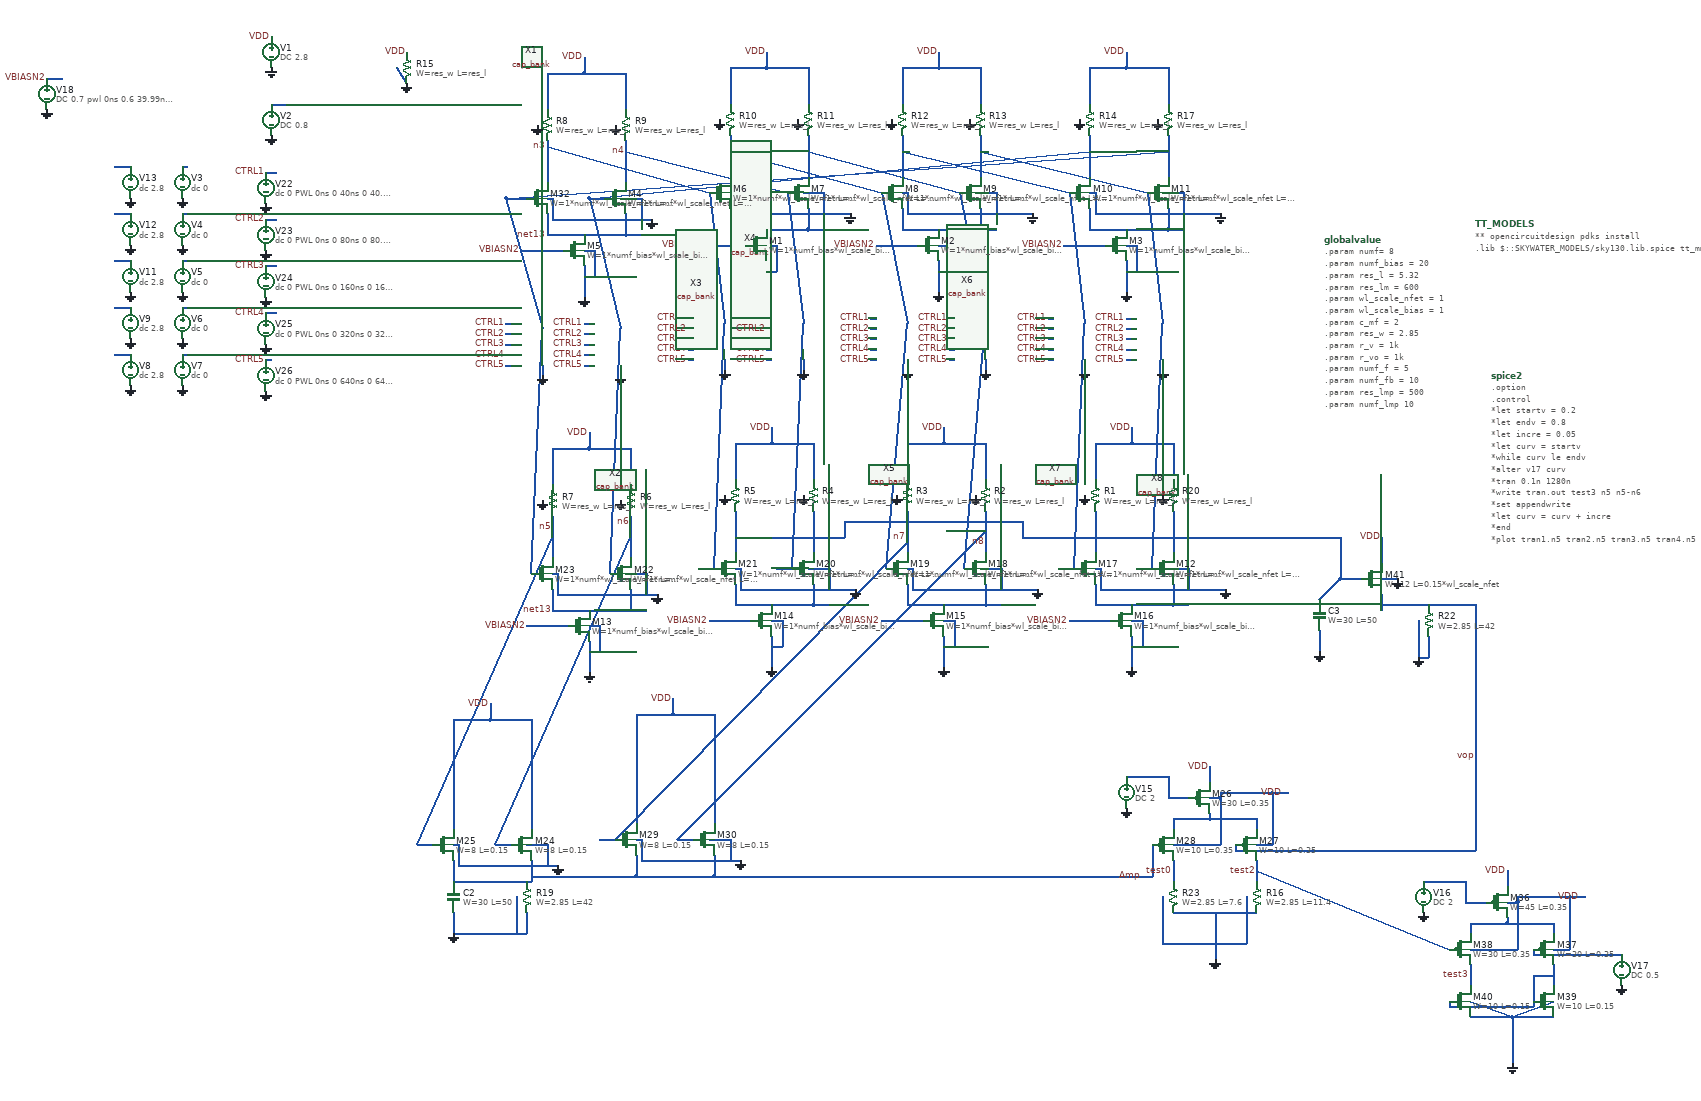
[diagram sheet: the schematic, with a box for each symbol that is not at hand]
v {xschem version=3.0.0 file_version=1.2 }
G {}
K {}
V {}
S {}
E {}
N 520 -180 520 -140 {
lab=GND}
N 450 -240 520 -240 {
lab=net13}
N 450 -280 450 -240 {
lab=net13}
N 520 -240 600 -240 {
lab=net13}
N 600 -280 600 -240 {
lab=net13}
N 600 -420 600 -340 {
lab=n4}
N 600 -550 600 -480 {
lab=VDD}
N 520 -550 600 -550 {
lab=VDD}
N 520 -580 520 -550 {
lab=VDD}
N 450 -550 520 -550 {
lab=VDD}
N 450 -550 450 -480 {
lab=VDD}
N 450 -420 450 -340 {
lab=n3}
N 380 -310 410 -310 {
lab=#net1}
N 530 -310 560 -310 {
lab=#net2}
N 400 -210 480 -210 {
lab=VBIASN2}
N 450 -310 460 -310 {
lab=GND}
N 520 -140 520 -120 {
lab=GND}
N 520 -210 540 -210 {
lab=GND}
N 540 -210 540 -160 {
lab=GND}
N 520 -160 540 -160 {
lab=GND}
N 590 -310 600 -310 {
lab=GND}
N 600 -310 630 -310 {
lab=GND}
N 600 -240 630 -240 {
lab=net13}
N 870 -190 870 -150 {
lab=GND}
N 800 -250 870 -250 {
lab=#net3}
N 800 -290 800 -250 {
lab=#net3}
N 870 -250 950 -250 {
lab=#net3}
N 950 -290 950 -250 {
lab=#net3}
N 950 -430 950 -350 {
lab=#net4}
N 950 -560 950 -490 {
lab=VDD}
N 870 -560 950 -560 {
lab=VDD}
N 870 -590 870 -560 {
lab=VDD}
N 800 -560 870 -560 {
lab=VDD}
N 800 -560 800 -490 {
lab=VDD}
N 800 -430 800 -350 {
lab=#net5}
N 750 -220 830 -220 {
lab=VBIASN2}
N 800 -320 810 -320 {
lab=GND}
N 870 -150 870 -130 {
lab=GND}
N 870 -220 890 -220 {
lab=GND}
N 890 -220 890 -170 {
lab=GND}
N 870 -170 890 -170 {
lab=GND}
N 940 -320 950 -320 {
lab=GND}
N 950 -320 980 -320 {
lab=GND}
N 950 -250 980 -250 {
lab=#net3}
N 1200 -190 1200 -150 {
lab=GND}
N 1130 -250 1200 -250 {
lab=#net6}
N 1130 -290 1130 -250 {
lab=#net6}
N 1200 -250 1280 -250 {
lab=#net6}
N 1280 -290 1280 -250 {
lab=#net6}
N 1280 -430 1280 -350 {
lab=#net7}
N 1280 -560 1280 -490 {
lab=VDD}
N 1200 -560 1280 -560 {
lab=VDD}
N 1200 -590 1200 -560 {
lab=VDD}
N 1130 -560 1200 -560 {
lab=VDD}
N 1130 -560 1130 -490 {
lab=VDD}
N 1130 -430 1130 -350 {
lab=#net8}
N 1080 -220 1160 -220 {
lab=VBIASN2}
N 1130 -320 1140 -320 {
lab=GND}
N 1200 -150 1200 -130 {
lab=GND}
N 1200 -220 1220 -220 {
lab=GND}
N 1220 -220 1220 -170 {
lab=GND}
N 1200 -170 1220 -170 {
lab=GND}
N 1270 -320 1280 -320 {
lab=GND}
N 1280 -320 1310 -320 {
lab=GND}
N 1280 -250 1310 -250 {
lab=#net6}
N 460 -310 460 -270 {
lab=GND}
N 460 -270 650 -270 {
lab=GND}
N 630 -310 630 -270 {
lab=GND}
N 810 -320 810 -280 {
lab=GND}
N 810 -280 1030 -280 {
lab=GND}
N 980 -320 980 -280 {
lab=GND}
N 1140 -320 1140 -280 {
lab=GND}
N 1140 -280 1380 -280 {
lab=GND}
N 1310 -320 1310 -280 {
lab=GND}
N 1560 -190 1560 -150 {
lab=GND}
N 1490 -250 1560 -250 {
lab=#net9}
N 1490 -290 1490 -250 {
lab=#net9}
N 1560 -250 1640 -250 {
lab=#net9}
N 1640 -290 1640 -250 {
lab=#net9}
N 1640 -430 1640 -350 {
lab=#net1}
N 1640 -560 1640 -490 {
lab=VDD}
N 1560 -560 1640 -560 {
lab=VDD}
N 1560 -590 1560 -560 {
lab=VDD}
N 1490 -560 1560 -560 {
lab=VDD}
N 1490 -560 1490 -490 {
lab=VDD}
N 1490 -430 1490 -350 {
lab=#net2}
N 1440 -220 1520 -220 {
lab=VBIASN2}
N 1490 -320 1500 -320 {
lab=GND}
N 1560 -150 1560 -130 {
lab=GND}
N 1560 -220 1580 -220 {
lab=GND}
N 1580 -220 1580 -170 {
lab=GND}
N 1560 -170 1580 -170 {
lab=GND}
N 1630 -320 1640 -320 {
lab=GND}
N 1640 -320 1670 -320 {
lab=GND}
N 1640 -250 1670 -250 {
lab=#net9}
N 1500 -320 1500 -280 {
lab=GND}
N 1500 -280 1740 -280 {
lab=GND}
N 1670 -320 1670 -280 {
lab=GND}
N -80 -490 -50 -490 {
lab=#net10}
N -250 -370 -240 -370 {
lab=#net11}
N -250 -280 -240 -280 {
lab=#net12}
N -250 -190 -240 -190 {
lab=#net14}
N -250 -100 -240 -100 {
lab=#net15}
N -250 -10 -240 -10 {
lab=#net16}
N 530 540 530 580 {
lab=GND}
N 460 480 530 480 {
lab=net13}
N 460 440 460 480 {
lab=net13}
N 530 480 610 480 {
lab=net13}
N 610 440 610 480 {
lab=net13}
N 610 300 610 380 {
lab=n6}
N 610 170 610 240 {
lab=VDD}
N 530 170 610 170 {
lab=VDD}
N 530 140 530 170 {
lab=VDD}
N 460 170 530 170 {
lab=VDD}
N 460 170 460 240 {
lab=VDD}
N 460 300 460 380 {
lab=n5}
N 410 510 490 510 {
lab=VBIASN2}
N 460 410 470 410 {
lab=GND}
N 530 580 530 600 {
lab=GND}
N 530 510 550 510 {
lab=GND}
N 550 510 550 560 {
lab=GND}
N 530 560 550 560 {
lab=GND}
N 600 410 610 410 {
lab=GND}
N 610 410 640 410 {
lab=GND}
N 610 480 640 480 {
lab=net13}
N 880 530 880 570 {
lab=GND}
N 810 470 880 470 {
lab=#net17}
N 810 430 810 470 {
lab=#net17}
N 880 470 960 470 {
lab=#net17}
N 960 430 960 470 {
lab=#net17}
N 960 290 960 370 {
lab=#net18}
N 960 160 960 230 {
lab=VDD}
N 880 160 960 160 {
lab=VDD}
N 880 130 880 160 {
lab=VDD}
N 810 160 880 160 {
lab=VDD}
N 810 160 810 230 {
lab=VDD}
N 810 290 810 370 {
lab=#net18}
N 740 400 770 400 {
lab=n3}
N 890 400 920 400 {
lab=n4}
N 760 500 840 500 {
lab=VBIASN2}
N 810 400 820 400 {
lab=GND}
N 880 570 880 590 {
lab=GND}
N 880 500 900 500 {
lab=GND}
N 900 500 900 550 {
lab=GND}
N 880 550 900 550 {
lab=GND}
N 950 400 960 400 {
lab=GND}
N 960 400 990 400 {
lab=GND}
N 960 470 990 470 {
lab=#net17}
N 1210 530 1210 570 {
lab=GND}
N 1140 470 1210 470 {
lab=#net19}
N 1140 430 1140 470 {
lab=#net19}
N 1210 470 1290 470 {
lab=#net19}
N 1290 430 1290 470 {
lab=#net19}
N 1290 290 1290 370 {
lab=n8}
N 1290 160 1290 230 {
lab=VDD}
N 1210 160 1290 160 {
lab=VDD}
N 1210 130 1210 160 {
lab=VDD}
N 1140 160 1210 160 {
lab=VDD}
N 1140 160 1140 230 {
lab=VDD}
N 1140 290 1140 370 {
lab=n7}
N 1090 500 1170 500 {
lab=VBIASN2}
N 1140 400 1150 400 {
lab=GND}
N 1210 570 1210 590 {
lab=GND}
N 1210 500 1230 500 {
lab=GND}
N 1230 500 1230 550 {
lab=GND}
N 1210 550 1230 550 {
lab=GND}
N 1280 400 1290 400 {
lab=GND}
N 1290 400 1320 400 {
lab=GND}
N 1290 470 1320 470 {
lab=#net19}
N 470 410 470 450 {
lab=GND}
N 470 450 660 450 {
lab=GND}
N 640 410 640 450 {
lab=GND}
N 820 400 820 440 {
lab=GND}
N 820 440 1040 440 {
lab=GND}
N 990 400 990 440 {
lab=GND}
N 1150 400 1150 440 {
lab=GND}
N 1150 440 1390 440 {
lab=GND}
N 1320 400 1320 440 {
lab=GND}
N 1570 530 1570 570 {
lab=GND}
N 1500 470 1570 470 {
lab=#net20}
N 1500 430 1500 470 {
lab=#net20}
N 1570 470 1650 470 {
lab=#net20}
N 1650 430 1650 470 {
lab=#net20}
N 1650 290 1650 370 {
lab=#net18}
N 1650 160 1650 230 {
lab=VDD}
N 1570 160 1650 160 {
lab=VDD}
N 1570 130 1570 160 {
lab=VDD}
N 1500 160 1570 160 {
lab=VDD}
N 1500 160 1500 230 {
lab=VDD}
N 1500 290 1500 370 {
lab=#net18}
N 1430 400 1460 400 {
lab=#net8}
N 1580 400 1610 400 {
lab=#net7}
N 1450 500 1530 500 {
lab=VBIASN2}
N 1500 400 1510 400 {
lab=GND}
N 1570 570 1570 590 {
lab=GND}
N 1570 500 1590 500 {
lab=GND}
N 1590 500 1590 550 {
lab=GND}
N 1570 550 1590 550 {
lab=GND}
N 1640 400 1650 400 {
lab=GND}
N 1650 400 1680 400 {
lab=GND}
N 1650 470 1680 470 {
lab=#net20}
N 1510 400 1510 440 {
lab=GND}
N 1510 440 1750 440 {
lab=GND}
N 1680 400 1680 440 {
lab=GND}
N 420 410 440 -60 {
lab=#net1}
N 570 410 590 -60 {
lab=#net2}
N 770 400 790 -70 {
lab=n3}
N 920 400 940 -70 {
lab=n4}
N 1100 400 1140 -70 {
lab=#net5}
N 1250 400 1290 -70 {
lab=#net4}
N 1460 400 1480 -70 {
lab=#net8}
N 1610 400 1630 -70 {
lab=#net7}
N 810 340 960 340 {
lab=#net18}
N 1500 340 1650 340 {
lab=#net18}
N 270 960 270 1000 {
lab=Amp}
N 340 1000 420 1000 {
lab=Amp}
N 420 960 420 1000 {
lab=Amp}
N 420 820 420 900 {
lab=VDD}
N 420 690 420 760 {
lab=VDD}
N 340 690 420 690 {
lab=VDD}
N 340 660 340 690 {
lab=VDD}
N 270 690 340 690 {
lab=VDD}
N 270 690 270 760 {
lab=VDD}
N 270 820 270 900 {
lab=VDD}
N 200 930 230 930 {
lab=n5}
N 350 930 380 930 {
lab=n6}
N 270 930 280 930 {
lab=GND}
N 410 930 420 930 {
lab=GND}
N 420 930 450 930 {
lab=GND}
N 280 930 280 970 {
lab=GND}
N 280 970 470 970 {
lab=GND}
N 450 930 450 970 {
lab=GND}
N 270 1060 270 1100 {
lab=GND}
N 270 1000 340 1000 {
lab=Amp}
N 270 760 270 820 {
lab=VDD}
N 420 760 420 820 {
lab=VDD}
N 410 1060 410 1100 {
lab=GND}
N 340 1100 410 1100 {
lab=GND}
N 270 1100 340 1100 {
lab=GND}
N 620 950 620 990 {
lab=Amp}
N 690 990 770 990 {
lab=Amp}
N 770 950 770 990 {
lab=Amp}
N 770 810 770 890 {
lab=VDD}
N 770 680 770 750 {
lab=VDD}
N 690 680 770 680 {
lab=VDD}
N 690 650 690 680 {
lab=VDD}
N 620 680 690 680 {
lab=VDD}
N 620 680 620 750 {
lab=VDD}
N 620 810 620 890 {
lab=VDD}
N 550 920 580 920 {
lab=n7}
N 700 920 730 920 {
lab=n8}
N 620 920 630 920 {
lab=GND}
N 760 920 770 920 {
lab=GND}
N 770 920 800 920 {
lab=GND}
N 630 920 630 960 {
lab=GND}
N 630 960 820 960 {
lab=GND}
N 800 920 800 960 {
lab=GND}
N 620 990 690 990 {
lab=Amp}
N 620 750 620 810 {
lab=VDD}
N 770 750 770 810 {
lab=VDD}
N 420 990 620 990 {
lab=Amp}
N 770 990 950 990 {
lab=Amp}
N 1720 780 1720 810 {
lab=VDD}
N 1560 800 1640 800 {
lab=#net21}
N 1640 800 1640 840 {
lab=#net21}
N 1640 840 1680 840 {
lab=#net21}
N 1460 990 1610 990 {
lab=Amp}
N 1610 930 1610 990 {
lab=Amp}
N 1720 870 1720 880 {
lab=#net22}
N 1650 880 1720 880 {
lab=#net22}
N 1650 880 1650 900 {
lab=#net22}
N 1720 880 1810 880 {
lab=#net22}
N 1810 880 1810 900 {
lab=#net22}
N 1650 960 1650 1000 {
lab=test0}
N 1810 960 1810 1000 {
lab=test2}
N 1650 1060 1810 1060 {
lab=GND}
N 1730 1060 1730 1080 {
lab=GND}
N 1840 830 1870 830 {
lab=VDD}
N 1840 830 1840 930 {
lab=VDD}
N 1810 930 1840 930 {
lab=VDD}
N 1740 830 1840 830 {
lab=VDD}
N 1740 830 1740 840 {
lab=VDD}
N 1720 840 1740 840 {
lab=VDD}
N 1740 840 1740 930 {
lab=VDD}
N 1650 930 1740 930 {
lab=VDD}
N 1730 1080 1730 1150 {
lab=GND}
N 2290 980 2290 1010 {
lab=VDD}
N 2130 1000 2210 1000 {
lab=#net23}
N 2210 1000 2210 1040 {
lab=#net23}
N 2210 1040 2250 1040 {
lab=#net23}
N 2290 1070 2290 1080 {
lab=#net24}
N 2220 1080 2290 1080 {
lab=#net24}
N 2220 1080 2220 1100 {
lab=#net24}
N 2290 1080 2380 1080 {
lab=#net24}
N 2380 1080 2380 1100 {
lab=#net24}
N 2340 1130 2340 1140 {
lab=#net25}
N 2340 1140 2510 1140 {
lab=#net25}
N 2220 1160 2220 1200 {
lab=test3}
N 2380 1160 2380 1200 {
lab=#net26}
N 2220 1260 2380 1260 {
lab=GND}
N 2300 1260 2300 1280 {
lab=GND}
N 2410 1030 2440 1030 {
lab=VDD}
N 2410 1030 2410 1130 {
lab=VDD}
N 2380 1130 2410 1130 {
lab=VDD}
N 2310 1030 2410 1030 {
lab=VDD}
N 2310 1030 2310 1040 {
lab=VDD}
N 2290 1040 2310 1040 {
lab=VDD}
N 2310 1040 2310 1130 {
lab=VDD}
N 2220 1130 2310 1130 {
lab=VDD}
N 2300 1280 2300 1350 {
lab=GND}
N 2340 1180 2340 1230 {
lab=#net26}
N 2340 1180 2380 1180 {
lab=#net26}
N 2340 1230 2340 1240 {
lab=#net26}
N 2180 1240 2340 1240 {
lab=#net26}
N 2180 1230 2180 1240 {
lab=#net26}
N 2220 1230 2300 1260 {
lab=GND}
N 2300 1260 2380 1230 {
lab=GND}
N 1810 980 2180 1130 {
lab=test2}
N 2140 530 2140 570 {
lab=GND}
N 2050 340 2050 380 {
lab=VDD}
N 2050 380 2050 390 {
lab=VDD}
N 2050 450 2050 480 {
lab=vop}
N 2050 470 2140 470 {
lab=vop}
N 2050 420 2080 420 {
lab=GND}
N 1930 520 1930 560 {
lab=GND}
N 2140 470 2230 470 {
lab=vop}
N 1650 340 1970 340 {
lab=#net18}
N 1970 340 1970 420 {
lab=#net18}
N 2230 470 2230 940 {
lab=vop}
N -510 -540 -480 -540 {
lab=VBIASN2}
N -90 0 -80 0 {
lab=CTRL5}
N -90 -90 -70 -90 {
lab=CTRL4}
N -90 -180 -70 -180 {
lab=CTRL3}
N -90 -270 -70 -270 {
lab=CTRL2}
N -90 -360 -70 -360 {
lab=CTRL1}
N 440 10 440 30 {
lab=GND}
N 370 10 380 10 {
lab=CTRL5}
N 370 -10 380 -10 {
lab=CTRL4}
N 370 -30 380 -30 {
lab=CTRL3}
N 370 -50 380 -50 {
lab=CTRL2}
N 370 -70 380 -70 {
lab=CTRL1}
N 590 10 590 30 {
lab=GND}
N 520 10 530 10 {
lab=CTRL5}
N 520 -10 530 -10 {
lab=CTRL4}
N 520 -30 530 -30 {
lab=CTRL3}
N 520 -50 530 -50 {
lab=CTRL2}
N 520 -70 530 -70 {
lab=CTRL1}
N 790 0 790 20 {
lab=GND}
N 720 0 730 0 {
lab=CTRL5}
N 720 -20 730 -20 {
lab=CTRL4}
N 720 -40 730 -40 {
lab=CTRL3}
N 720 -60 730 -60 {
lab=CTRL2}
N 720 -80 730 -80 {
lab=CTRL1}
N 940 0 940 20 {
lab=GND}
N 870 0 880 0 {
lab=CTRL5}
N 870 -20 880 -20 {
lab=CTRL4}
N 870 -40 880 -40 {
lab=CTRL3}
N 870 -60 880 -60 {
lab=CTRL2}
N 870 -80 880 -80 {
lab=CTRL1}
N 1140 0 1140 20 {
lab=GND}
N 1070 0 1080 0 {
lab=CTRL5}
N 1070 -20 1080 -20 {
lab=CTRL4}
N 1070 -40 1080 -40 {
lab=CTRL3}
N 1070 -60 1080 -60 {
lab=CTRL2}
N 1070 -80 1080 -80 {
lab=CTRL1}
N 1290 0 1290 20 {
lab=GND}
N 1220 0 1230 0 {
lab=CTRL5}
N 1220 -20 1230 -20 {
lab=CTRL4}
N 1220 -40 1230 -40 {
lab=CTRL3}
N 1220 -60 1230 -60 {
lab=CTRL2}
N 1220 -80 1230 -80 {
lab=CTRL1}
N 1480 0 1480 20 {
lab=GND}
N 1410 0 1420 0 {
lab=CTRL5}
N 1410 -20 1420 -20 {
lab=CTRL4}
N 1410 -40 1420 -40 {
lab=CTRL3}
N 1410 -60 1420 -60 {
lab=CTRL2}
N 1410 -80 1420 -80 {
lab=CTRL1}
N 1630 0 1630 20 {
lab=GND}
N 1560 0 1570 0 {
lab=CTRL5}
N 1560 -20 1570 -20 {
lab=CTRL4}
N 1560 -40 1570 -40 {
lab=CTRL3}
N 1560 -60 1570 -60 {
lab=CTRL2}
N 1560 -80 1570 -80 {
lab=CTRL1}
N 1930 460 1970 420 {
lab=#net18}
N 1970 420 2010 420 {
lab=#net18}
N 2120 500 2120 570 {
lab=GND}
N 1630 1030 1630 1120 {
lab=GND}
N 1630 1120 1730 1120 {
lab=GND}
N 1790 1030 1790 1120 {
lab=GND}
N 1730 1120 1790 1120 {
lab=GND}
N 390 1030 390 1100 {
lab=GND}
N 160 -560 180 -530 {
lab=GND}
N -380 -370 -350 -370 {
lab=#net27}
N -380 -280 -350 -280 {
lab=#net28}
N -380 -190 -350 -190 {
lab=#net29}
N -380 -100 -350 -100 {
lab=#net30}
N -380 -10 -350 -10 {
lab=#net31}
N 960 340 1020 340 {
lab=#net18}
N 1020 310 1020 340 {
lab=#net18}
N 1020 310 1360 310 {
lab=#net18}
N 1360 310 1360 340 {
lab=#net18}
N 1360 340 1500 340 {
lab=#net18}
N 200 930 460 340 {
lab=n5}
N 350 930 610 340 {
lab=n6}
N 700 920 1290 330 {
lab=n8}
N 950 990 1470 990 {
lab=Amp}
N 450 -410 760 -320 {
lab=n3}
N 600 -400 910 -320 {
lab=n4}
N 800 -400 1090 -320 {
lab=#net5}
N 950 -400 1240 -320 {
lab=#net4}
N 1130 -400 1450 -320 {
lab=#net8}
N 1280 -400 1600 -320 {
lab=#net7}
N 530 -310 1490 -400 {
lab=#net2}
N 370 -310 1640 -400 {
lab=#net1}
N 370 -310 380 -310 {
lab=#net1}
N 370 -310 440 -60 {
lab=#net1}
N 530 -310 590 -60 {
lab=#net2}
N 760 -320 790 -70 {
lab=n3}
N 910 -320 940 -70 {
lab=n4}
N 1090 -320 1140 -70 {
lab=#net5}
N 1240 -320 1290 -70 {
lab=#net4}
N 1450 -320 1480 -70 {
lab=#net8}
N 1600 -320 1630 -70 {
lab=#net7}
N 580 920 1140 350 {
lab=n7}
N 2120 570 2140 570 {
lab=GND}
N 1770 930 1770 940 {
lab=vop}
N 1770 940 2230 940 {
lab=vop}
N -90 0 -80 0 {
lab=CTRL5}
N -90 -90 -70 -90 {
lab=CTRL4}
N -90 -180 -70 -180 {
lab=CTRL3}
N -90 -270 -70 -270 {
lab=CTRL2}
N -90 -360 -70 -360 {
lab=CTRL1}
C {code.sym} 2230 -260 0 0 {name=TT_MODELS
only_toplevel=true
format="tcleval( @value )"
value="
** opencircuitdesign pdks install
.lib $::SKYWATER_MODELS/sky130.lib.spice tt_mm

"
spice_ignore=false}
C {vsource.sym} -80 -590 0 0 {name=V1 value="DC 2.8"}
C {gnd.sym} -80 -560 0 0 {name=l12 lab=GND}
C {vsource.sym} -80 -460 0 0 {name=V2 value="DC 0.8" 
}
C {gnd.sym} -80 -430 0 0 {name=l15 lab=GND}
C {lab_pin.sym} -80 -620 0 0 {name=l18 sig_type=std_logic lab=VDD
}
C {lab_pin.sym} -510 -540 0 0 {name=l21 sig_type=std_logic lab=VBIASN2
}
C {code_shown.sym} 1940 -230 0 0 {name=globalvalue only_toplevel=false value="
.param numf= 8
.param numf_bias = 20
.param res_l = 5.32
.param res_lm = 600
.param wl_scale_nfet = 1
.param wl_scale_bias = 1
.param c_mf = 2
.param res_w = 2.85
.param r_v = 1k
.param r_vo = 1k
.param numf_f = 5
.param numf_fb = 10
.param res_lmp = 500
.param numf_lmp 10
.param numf_a = 20
"}
C {gnd.sym} 520 -120 0 0 {name=l2 lab=GND}
C {lab_pin.sym} 520 -580 0 0 {name=l8 sig_type=std_logic lab=VDD
}
C {gnd.sym} 870 -130 0 0 {name=l26 lab=GND}
C {lab_pin.sym} 870 -590 0 0 {name=l39 sig_type=std_logic lab=VDD
}
C {gnd.sym} 1200 -130 0 0 {name=l45 lab=GND}
C {lab_pin.sym} 1200 -590 0 0 {name=l46 sig_type=std_logic lab=VDD
}
C {lab_pin.sym} 400 -210 0 0 {name=l48 sig_type=std_logic lab=VBIASN2}
C {lab_pin.sym} 750 -220 0 0 {name=l49 sig_type=std_logic lab=VBIASN2}
C {lab_pin.sym} 1080 -220 0 0 {name=l50 sig_type=std_logic lab=VBIASN2}
C {lab_pin.sym} 450 -240 0 0 {name=l51 sig_type=std_logic lab=net13}
C {gnd.sym} 1560 -130 0 0 {name=l52 lab=GND}
C {lab_pin.sym} 1560 -590 0 0 {name=l53 sig_type=std_logic lab=VDD
}
C {lab_pin.sym} 1440 -220 0 0 {name=l55 sig_type=std_logic lab=VBIASN2}
C {lab_pin.sym} 450 -410 0 0 {name=l58 sig_type=std_logic lab=n3}
C {lab_pin.sym} 600 -400 0 0 {name=l60 sig_type=std_logic lab=n4}
C {vsource.sym} -250 -340 0 0 {name=V3 value="dc 0"}
C {gnd.sym} -250 -310 0 0 {name=l24 lab=GND}
C {gnd.sym} -250 -220 0 0 {name=l29 lab=GND}
C {gnd.sym} -250 -130 0 0 {name=l31 lab=GND}
C {gnd.sym} -250 -40 0 0 {name=l33 lab=GND}
C {gnd.sym} -250 50 0 0 {name=l35 lab=GND}
C {vsource.sym} -250 -250 0 0 {name=V4 value="dc 0" 
}
C {vsource.sym} -250 -160 0 0 {name=V5 value="dc 0" 
}
C {vsource.sym} -250 -70 0 0 {name=V6 value="dc 0" 
}
C {vsource.sym} -250 20 0 0 {name=V7 value="dc 0"
}
C {gnd.sym} 650 -270 0 0 {name=l17 lab=GND}
C {gnd.sym} 1030 -280 0 0 {name=l37 lab=GND}
C {gnd.sym} 1380 -280 0 0 {name=l38 lab=GND}
C {gnd.sym} 1740 -280 0 0 {name=l40 lab=GND}
C {lab_pin.sym} 530 140 0 0 {name=l1 sig_type=std_logic lab=VDD
}
C {lab_pin.sym} 880 130 0 0 {name=l4 sig_type=std_logic lab=VDD
}
C {lab_pin.sym} 1210 130 0 0 {name=l6 sig_type=std_logic lab=VDD
}
C {lab_pin.sym} 760 500 0 0 {name=l9 sig_type=std_logic lab=VBIASN2}
C {lab_pin.sym} 1090 500 0 0 {name=l10 sig_type=std_logic lab=VBIASN2}
C {sky130_fd_pr/nfet_01v8_lvt.sym} 510 510 0 0 {name=M13
L=0.15*wl_scale_bias
W=1*numf_bias*wl_scale_bias
nf=1*numf_bias*wl_scale_bias
mult=1
ad="'int((nf+1)/2) * W/nf * 0.29'" 
pd="'2*int((nf+1)/2) * (W/nf + 0.29)'"
as="'int((nf+2)/2) * W/nf * 0.29'" 
ps="'2*int((nf+2)/2) * (W/nf + 0.29)'"
nrd="'0.29 / W'" nrs="'0.29 / W'"
sa=0 sb=0 sd=0
model=nfet_01v8_lvt
spiceprefix=X
}
C {sky130_fd_pr/nfet_01v8_lvt.sym} 860 500 0 0 {name=M14
L=0.15*wl_scale_bias
W=1*numf_bias*wl_scale_bias
nf=1*numf_bias*wl_scale_bias
mult=1
ad="'int((nf+1)/2) * W/nf * 0.29'" 
pd="'2*int((nf+1)/2) * (W/nf + 0.29)'"
as="'int((nf+2)/2) * W/nf * 0.29'" 
ps="'2*int((nf+2)/2) * (W/nf + 0.29)'"
nrd="'0.29 / W'" nrs="'0.29 / W'"
sa=0 sb=0 sd=0
model=nfet_01v8_lvt
spiceprefix=X
}
C {sky130_fd_pr/nfet_01v8_lvt.sym} 1190 500 0 0 {name=M15
L=0.15*wl_scale_bias
W=1*numf_bias*wl_scale_bias
nf=1*numf_bias*wl_scale_bias
mult=1
ad="'int((nf+1)/2) * W/nf * 0.29'" 
pd="'2*int((nf+1)/2) * (W/nf + 0.29)'"
as="'int((nf+2)/2) * W/nf * 0.29'" 
ps="'2*int((nf+2)/2) * (W/nf + 0.29)'"
nrd="'0.29 / W'" nrs="'0.29 / W'"
sa=0 sb=0 sd=0
model=nfet_01v8_lvt
spiceprefix=X
}
C {lab_pin.sym} 460 480 0 0 {name=l11 sig_type=std_logic lab=net13}
C {lab_pin.sym} 1570 130 0 0 {name=l13 sig_type=std_logic lab=VDD
}
C {lab_pin.sym} 1450 500 0 0 {name=l16 sig_type=std_logic lab=VBIASN2}
C {sky130_fd_pr/nfet_01v8_lvt.sym} 1550 500 0 0 {name=M16
L=0.15*wl_scale_bias
W=1*numf_bias*wl_scale_bias
nf=1*numf_bias*wl_scale_bias
mult=1
ad="'int((nf+1)/2) * W/nf * 0.29'" 
pd="'2*int((nf+1)/2) * (W/nf + 0.29)'"
as="'int((nf+2)/2) * W/nf * 0.29'" 
ps="'2*int((nf+2)/2) * (W/nf + 0.29)'"
nrd="'0.29 / W'" nrs="'0.29 / W'"
sa=0 sb=0 sd=0
model=nfet_01v8_lvt
spiceprefix=X
}
C {gnd.sym} 660 450 0 0 {name=l22 lab=GND}
C {gnd.sym} 1040 440 0 0 {name=l23 lab=GND}
C {gnd.sym} 1390 440 0 0 {name=l28 lab=GND}
C {gnd.sym} 1750 440 0 0 {name=l34 lab=GND}
C {lab_pin.sym} 410 510 0 0 {name=l41 sig_type=std_logic lab=VBIASN2}
C {gnd.sym} 530 600 0 0 {name=l121 lab=GND}
C {gnd.sym} 880 590 0 0 {name=l122 lab=GND}
C {gnd.sym} 1210 590 0 0 {name=l123 lab=GND}
C {gnd.sym} 1570 590 0 0 {name=l124 lab=GND}
C {lab_pin.sym} 340 660 0 0 {name=l125 sig_type=std_logic lab=VDD
}
C {gnd.sym} 470 970 0 0 {name=l126 lab=GND}
C {gnd.sym} 270 1100 0 0 {name=l127 lab=GND}
C {sky130_fd_pr/nfet_01v8_lvt.sym} 250 930 0 0 {name=M25
L=0.15
W=8
nf=8
mult=1
ad="'int((nf+1)/2) * W/nf * 0.29'" 
pd="'2*int((nf+1)/2) * (W/nf + 0.29)'"
as="'int((nf+2)/2) * W/nf * 0.29'" 
ps="'2*int((nf+2)/2) * (W/nf + 0.29)'"
nrd="'0.29 / W'" nrs="'0.29 / W'"
sa=0 sb=0 sd=0
model=nfet_01v8_lvt
spiceprefix=X
}
C {sky130_fd_pr/cap_mim_m3_1.sym} 270 1030 0 0 {name=C2 model=cap_mim_m3_1 W=30 L=50 MF=1 spiceprefix=X}
C {lab_pin.sym} 690 650 0 0 {name=l128 sig_type=std_logic lab=VDD
}
C {gnd.sym} 820 960 0 0 {name=l129 lab=GND}
C {lab_pin.sym} 1720 780 0 0 {name=l134 sig_type=std_logic lab=VDD
}
C {sky130_fd_pr/pfet_01v8_lvt.sym} 1700 840 0 0 {name=M26
L=0.35
W=30
nf=30
mult=1
ad="'int((nf+1)/2) * W/nf * 0.29'" 
pd="'2*int((nf+1)/2) * (W/nf + 0.29)'"
as="'int((nf+2)/2) * W/nf * 0.29'" 
ps="'2*int((nf+2)/2) * (W/nf + 0.29)'"
nrd="'0.29 / W'" nrs="'0.29 / W'"
sa=0 sb=0 sd=0
model=pfet_01v8_lvt
spiceprefix=X
}
C {sky130_fd_pr/pfet_01v8_lvt.sym} 1790 930 0 0 {name=M27
L=0.35
W=10
nf=10
mult=1
ad="'int((nf+1)/2) * W/nf * 0.29'" 
pd="'2*int((nf+1)/2) * (W/nf + 0.29)'"
as="'int((nf+2)/2) * W/nf * 0.29'" 
ps="'2*int((nf+2)/2) * (W/nf + 0.29)'"
nrd="'0.29 / W'" nrs="'0.29 / W'"
sa=0 sb=0 sd=0
model=pfet_01v8_lvt
spiceprefix=X
}
C {sky130_fd_pr/pfet_01v8_lvt.sym} 1630 930 0 0 {name=M28
L=0.35
W=10
nf=10
mult=1
ad="'int((nf+1)/2) * W/nf * 0.29'" 
pd="'2*int((nf+1)/2) * (W/nf + 0.29)'"
as="'int((nf+2)/2) * W/nf * 0.29'" 
ps="'2*int((nf+2)/2) * (W/nf + 0.29)'"
nrd="'0.29 / W'" nrs="'0.29 / W'"
sa=0 sb=0 sd=0
model=pfet_01v8_lvt
spiceprefix=X
}
C {vsource.sym} 1560 830 0 0 {name=V15 value="DC 2" 
}
C {gnd.sym} 1560 860 0 0 {name=l135 lab=GND}
C {gnd.sym} 1730 1150 0 0 {name=l136 lab=GND}
C {lab_pin.sym} 1590 990 0 0 {name=l137 sig_type=std_logic lab=Amp}
C {lab_pin.sym} 1860 830 0 0 {name=l138 sig_type=std_logic lab=VDD
}
C {lab_pin.sym} 2230 760 0 0 {name=l139 sig_type=std_logic lab=vop
}
C {lab_pin.sym} 1650 980 0 0 {name=l140 sig_type=std_logic lab=test0}
C {lab_pin.sym} 1810 980 0 0 {name=l141 sig_type=std_logic lab=test2}
C {lab_pin.sym} 2290 980 0 0 {name=l142 sig_type=std_logic lab=VDD
}
C {sky130_fd_pr/pfet_01v8_lvt.sym} 2270 1040 0 0 {name=M36
L=0.35
W=45
nf=45
mult=1
ad="'int((nf+1)/2) * W/nf * 0.29'" 
pd="'2*int((nf+1)/2) * (W/nf + 0.29)'"
as="'int((nf+2)/2) * W/nf * 0.29'" 
ps="'2*int((nf+2)/2) * (W/nf + 0.29)'"
nrd="'0.29 / W'" nrs="'0.29 / W'"
sa=0 sb=0 sd=0
model=pfet_01v8_lvt
spiceprefix=X
}
C {sky130_fd_pr/pfet_01v8_lvt.sym} 2360 1130 0 0 {name=M37
L=0.35
W=30
nf=30
mult=1
ad="'int((nf+1)/2) * W/nf * 0.29'" 
pd="'2*int((nf+1)/2) * (W/nf + 0.29)'"
as="'int((nf+2)/2) * W/nf * 0.29'" 
ps="'2*int((nf+2)/2) * (W/nf + 0.29)'"
nrd="'0.29 / W'" nrs="'0.29 / W'"
sa=0 sb=0 sd=0
model=pfet_01v8_lvt
spiceprefix=X
}
C {sky130_fd_pr/pfet_01v8_lvt.sym} 2200 1130 0 0 {name=M38
L=0.35
W=30
nf=30
mult=1
ad="'int((nf+1)/2) * W/nf * 0.29'" 
pd="'2*int((nf+1)/2) * (W/nf + 0.29)'"
as="'int((nf+2)/2) * W/nf * 0.29'" 
ps="'2*int((nf+2)/2) * (W/nf + 0.29)'"
nrd="'0.29 / W'" nrs="'0.29 / W'"
sa=0 sb=0 sd=0
model=pfet_01v8_lvt
spiceprefix=X
}
C {vsource.sym} 2130 1030 0 0 {name=V16 value="DC 2" 
}
C {gnd.sym} 2130 1060 0 0 {name=l143 lab=GND}
C {gnd.sym} 2300 1350 0 0 {name=l144 lab=GND}
C {lab_pin.sym} 2430 1030 0 0 {name=l145 sig_type=std_logic lab=VDD
}
C {sky130_fd_pr/nfet_01v8_lvt.sym} 2360 1230 0 0 {name=M39
L=0.15
W=10
nf=10
mult=1
ad="'int((nf+1)/2) * W/nf * 0.29'" 
pd="'2*int((nf+1)/2) * (W/nf + 0.29)'"
as="'int((nf+2)/2) * W/nf * 0.29'" 
ps="'2*int((nf+2)/2) * (W/nf + 0.29)'"
nrd="'0.29 / W'" nrs="'0.29 / W'"
sa=0 sb=0 sd=0
model=nfet_01v8_lvt
spiceprefix=X
}
C {sky130_fd_pr/nfet_01v8_lvt.sym} 2200 1230 0 0 {name=M40
L=0.15
W=10
nf=10
mult=1
ad="'int((nf+1)/2) * W/nf * 0.29'" 
pd="'2*int((nf+1)/2) * (W/nf + 0.29)'"
as="'int((nf+2)/2) * W/nf * 0.29'" 
ps="'2*int((nf+2)/2) * (W/nf + 0.29)'"
nrd="'0.29 / W'" nrs="'0.29 / W'"
sa=0 sb=0 sd=0
model=nfet_01v8_lvt
spiceprefix=X
}
C {vsource.sym} 2510 1170 0 0 {name=V17 value="DC 0.5" 
}
C {gnd.sym} 2510 1200 0 0 {name=l146 lab=GND}
C {lab_pin.sym} 2220 1180 0 0 {name=l147 sig_type=std_logic lab=test3}
C {gnd.sym} 2120 570 0 0 {name=l148 lab=GND}
C {sky130_fd_pr/nfet_01v8_lvt.sym} 2030 420 0 0 {name=M41
L=0.15*wl_scale_nfet
W=12
nf=12
mult=1
ad="'int((nf+1)/2) * W/nf * 0.29'" 
pd="'2*int((nf+1)/2) * (W/nf + 0.29)'"
as="'int((nf+2)/2) * W/nf * 0.29'" 
ps="'2*int((nf+2)/2) * (W/nf + 0.29)'"
nrd="'0.29 / W'" nrs="'0.29 / W'"
sa=0 sb=0 sd=0
model=nfet_01v8_lvt
spiceprefix=X
}
C {lab_pin.sym} 2050 340 0 0 {name=l149 sig_type=std_logic lab=VDD
}
C {gnd.sym} 2080 420 0 0 {name=l150 lab=GND}
C {gnd.sym} 1930 560 0 0 {name=l151 lab=GND}
C {sky130_fd_pr/cap_mim_m3_1.sym} 1930 490 0 0 {name=C3 model=cap_mim_m3_1 W=30 L=50 MF=1 spiceprefix=X}
C {vsource.sym} -510 -510 0 0 {name=V18 value="DC 0.7 pwl 0ns 0.6 39.99ns 1.2 40ns 0.7 r=0" }
C {gnd.sym} -510 -480 0 0 {name=l152 lab=GND}
C {gnd.sym} -90 -300 0 0 {name=l154 lab=GND}
C {gnd.sym} -90 -210 0 0 {name=l155 lab=GND}
C {gnd.sym} -90 -120 0 0 {name=l156 lab=GND}
C {gnd.sym} -90 -30 0 0 {name=l157 lab=GND}
C {gnd.sym} -90 60 0 0 {name=l158 lab=GND}
C {gnd.sym} 440 30 0 0 {name=l106 lab=GND}
C {lab_pin.sym} 370 -70 0 0 {name=l107 sig_type=std_logic lab=CTRL1}
C {lab_pin.sym} 370 -30 0 0 {name=l109 sig_type=std_logic lab=CTRL3}
C {lab_pin.sym} 370 -10 0 0 {name=l110 sig_type=std_logic lab=CTRL4}
C {lab_pin.sym} 370 10 0 0 {name=l111 sig_type=std_logic lab=CTRL5}
C {cap_bank.sym} 370 10 0 0 {name=X1}
C {lab_pin.sym} 370 -50 0 0 {name=l19 sig_type=std_logic lab=CTRL2}
C {gnd.sym} 590 30 0 0 {name=l3 lab=GND}
C {lab_pin.sym} 520 -70 0 0 {name=l5 sig_type=std_logic lab=CTRL1}
C {lab_pin.sym} 520 -30 0 0 {name=l7 sig_type=std_logic lab=CTRL3}
C {lab_pin.sym} 520 -10 0 0 {name=l14 sig_type=std_logic lab=CTRL4}
C {lab_pin.sym} 520 10 0 0 {name=l20 sig_type=std_logic lab=CTRL5}
C {cap_bank.sym} 520 10 0 0 {name=X2}
C {lab_pin.sym} 520 -50 0 0 {name=l25 sig_type=std_logic lab=CTRL2}
C {gnd.sym} 790 20 0 0 {name=l27 lab=GND}
C {lab_pin.sym} 720 -80 0 0 {name=l30 sig_type=std_logic lab=CTRL1}
C {lab_pin.sym} 720 -40 0 0 {name=l32 sig_type=std_logic lab=CTRL3}
C {lab_pin.sym} 720 -20 0 0 {name=l36 sig_type=std_logic lab=CTRL4}
C {lab_pin.sym} 720 0 0 0 {name=l43 sig_type=std_logic lab=CTRL5}
C {cap_bank.sym} 720 0 0 0 {name=X3}
C {lab_pin.sym} 720 -60 0 0 {name=l44 sig_type=std_logic lab=CTRL2}
C {gnd.sym} 940 20 0 0 {name=l47 lab=GND}
C {lab_pin.sym} 870 -80 0 0 {name=l54 sig_type=std_logic lab=CTRL1}
C {lab_pin.sym} 870 -40 0 0 {name=l56 sig_type=std_logic lab=CTRL3}
C {lab_pin.sym} 870 -20 0 0 {name=l57 sig_type=std_logic lab=CTRL4}
C {lab_pin.sym} 870 0 0 0 {name=l59 sig_type=std_logic lab=CTRL5}
C {cap_bank.sym} 870 0 0 0 {name=X4}
C {lab_pin.sym} 870 -60 0 0 {name=l61 sig_type=std_logic lab=CTRL2}
C {gnd.sym} 1140 20 0 0 {name=l62 lab=GND}
C {lab_pin.sym} 1070 -80 0 0 {name=l63 sig_type=std_logic lab=CTRL1}
C {lab_pin.sym} 1070 -40 0 0 {name=l64 sig_type=std_logic lab=CTRL3}
C {lab_pin.sym} 1070 -20 0 0 {name=l65 sig_type=std_logic lab=CTRL4}
C {lab_pin.sym} 1070 0 0 0 {name=l66 sig_type=std_logic lab=CTRL5}
C {cap_bank.sym} 1070 0 0 0 {name=X5}
C {lab_pin.sym} 1070 -60 0 0 {name=l67 sig_type=std_logic lab=CTRL2}
C {gnd.sym} 1290 20 0 0 {name=l68 lab=GND}
C {lab_pin.sym} 1220 -80 0 0 {name=l69 sig_type=std_logic lab=CTRL1}
C {lab_pin.sym} 1220 -40 0 0 {name=l70 sig_type=std_logic lab=CTRL3}
C {lab_pin.sym} 1220 -20 0 0 {name=l71 sig_type=std_logic lab=CTRL4}
C {lab_pin.sym} 1220 0 0 0 {name=l72 sig_type=std_logic lab=CTRL5}
C {cap_bank.sym} 1220 0 0 0 {name=X6}
C {lab_pin.sym} 1220 -60 0 0 {name=l73 sig_type=std_logic lab=CTRL2}
C {gnd.sym} 1480 20 0 0 {name=l74 lab=GND}
C {lab_pin.sym} 1410 -80 0 0 {name=l75 sig_type=std_logic lab=CTRL1}
C {lab_pin.sym} 1410 -40 0 0 {name=l76 sig_type=std_logic lab=CTRL3}
C {lab_pin.sym} 1410 -20 0 0 {name=l77 sig_type=std_logic lab=CTRL4}
C {lab_pin.sym} 1410 0 0 0 {name=l78 sig_type=std_logic lab=CTRL5}
C {cap_bank.sym} 1410 0 0 0 {name=X7}
C {lab_pin.sym} 1410 -60 0 0 {name=l79 sig_type=std_logic lab=CTRL2}
C {gnd.sym} 1630 20 0 0 {name=l80 lab=GND}
C {lab_pin.sym} 1560 -80 0 0 {name=l81 sig_type=std_logic lab=CTRL1}
C {lab_pin.sym} 1560 -40 0 0 {name=l82 sig_type=std_logic lab=CTRL3}
C {lab_pin.sym} 1560 -20 0 0 {name=l83 sig_type=std_logic lab=CTRL4}
C {lab_pin.sym} 1560 0 0 0 {name=l84 sig_type=std_logic lab=CTRL5}
C {cap_bank.sym} 1560 0 0 0 {name=X8}
C {lab_pin.sym} 1560 -60 0 0 {name=l85 sig_type=std_logic lab=CTRL2}
C {gnd.sym} 1480 260 0 0 {name=l101 lab=GND}
C {gnd.sym} 1630 260 0 0 {name=l42 lab=GND}
C {gnd.sym} 1270 260 0 0 {name=l86 lab=GND}
C {gnd.sym} 1120 260 0 0 {name=l87 lab=GND}
C {gnd.sym} 1620 -460 0 0 {name=l88 lab=GND}
C {gnd.sym} 1470 -460 0 0 {name=l89 lab=GND}
C {gnd.sym} 1260 -460 0 0 {name=l90 lab=GND}
C {gnd.sym} 1110 -460 0 0 {name=l91 lab=GND}
C {gnd.sym} 930 -460 0 0 {name=l92 lab=GND}
C {gnd.sym} 780 -460 0 0 {name=l93 lab=GND}
C {gnd.sym} 790 260 0 0 {name=l94 lab=GND}
C {gnd.sym} 940 260 0 0 {name=l95 lab=GND}
C {gnd.sym} 590 270 0 0 {name=l96 lab=GND}
C {gnd.sym} 440 270 0 0 {name=l97 lab=GND}
C {gnd.sym} 430 -450 0 0 {name=l98 lab=GND}
C {gnd.sym} 580 -450 0 0 {name=l99 lab=GND}
C {sky130_fd_pr/res_high_po_2p85.sym} 2140 500 0 0 {name=R22
W=2.85
L=42
model=res_high_po_2p85
spiceprefix=X
mult=1}
C {sky130_fd_pr/res_high_po_2p85.sym} 1650 1030 0 0 {name=R23
W=2.85
L=7.6
model=res_high_po_2p85
spiceprefix=X
mult=1}
C {sky130_fd_pr/res_high_po_2p85.sym} 1810 1030 0 0 {name=R16
W=2.85
L=11.4
model=res_high_po_2p85
spiceprefix=X
mult=1}
C {sky130_fd_pr/res_high_po_2p85.sym} 410 1030 0 0 {name=R19
W=2.85
L=42
model=res_high_po_2p85
spiceprefix=X
mult=1}
C {sky130_fd_pr/res_high_po_2p85.sym} 180 -560 0 0 {name=R15
W=res_w
L=res_l
model=res_high_po_2p85
spiceprefix=X
mult=1}
C {gnd.sym} 180 -530 0 0 {name=l100 lab=GND}
C {lab_pin.sym} 180 -590 0 0 {name=l102 sig_type=std_logic lab=VDD
}
C {vsource.sym} -350 20 0 0 {name=V8 value="dc 2.8"
}
C {gnd.sym} -350 50 0 0 {name=l103 lab=GND}
C {vsource.sym} -350 -70 0 0 {name=V9 value="dc 2.8"
}
C {gnd.sym} -350 -40 0 0 {name=l104 lab=GND}
C {gnd.sym} -350 -40 0 0 {name=l105 lab=GND}
C {vsource.sym} -350 -160 0 0 {name=V11 value="dc 2.8"
}
C {gnd.sym} -350 -130 0 0 {name=l108 lab=GND}
C {vsource.sym} -350 -250 0 0 {name=V12 value="dc 2.8"
}
C {gnd.sym} -350 -220 0 0 {name=l112 lab=GND}
C {vsource.sym} -350 -340 0 0 {name=V13 value="dc 2.8"
}
C {gnd.sym} -350 -310 0 0 {name=l113 lab=GND}
C {sky130_fd_pr/res_high_po_2p85.sym} 1650 260 0 0 {name=R20
W=res_w
L=res_l
model=res_high_po_2p85
spiceprefix=X
mult=1}
C {sky130_fd_pr/res_high_po_2p85.sym} 1500 260 0 0 {name=R1
W=res_w
L=res_l
model=res_high_po_2p85
spiceprefix=X
mult=1}
C {sky130_fd_pr/res_high_po_2p85.sym} 1290 260 0 0 {name=R2
W=res_w
L=res_l
model=res_high_po_2p85
spiceprefix=X
mult=1}
C {sky130_fd_pr/res_high_po_2p85.sym} 1140 260 0 0 {name=R3
W=res_w
L=res_l
model=res_high_po_2p85
spiceprefix=X
mult=1}
C {sky130_fd_pr/res_high_po_2p85.sym} 960 260 0 0 {name=R4
W=res_w
L=res_l
model=res_high_po_2p85
spiceprefix=X
mult=1}
C {sky130_fd_pr/res_high_po_2p85.sym} 810 260 0 0 {name=R5
W=res_w
L=res_l
model=res_high_po_2p85
spiceprefix=X
mult=1}
C {sky130_fd_pr/res_high_po_2p85.sym} 610 270 0 0 {name=R6
W=res_w
L=res_l
model=res_high_po_2p85
spiceprefix=X
mult=1}
C {sky130_fd_pr/res_high_po_2p85.sym} 460 270 0 0 {name=R7
W=res_w
L=res_l
model=res_high_po_2p85
spiceprefix=X
mult=1}
C {sky130_fd_pr/res_high_po_2p85.sym} 450 -450 0 0 {name=R8
W=res_w
L=res_l
model=res_high_po_2p85
spiceprefix=X
mult=1}
C {sky130_fd_pr/res_high_po_2p85.sym} 600 -450 0 0 {name=R9
W=res_w
L=res_l
model=res_high_po_2p85
spiceprefix=X
mult=1}
C {sky130_fd_pr/res_high_po_2p85.sym} 800 -460 0 0 {name=R10
W=res_w
L=res_l
model=res_high_po_2p85
spiceprefix=X
mult=1}
C {sky130_fd_pr/res_high_po_2p85.sym} 950 -460 0 0 {name=R11
W=res_w
L=res_l
model=res_high_po_2p85
spiceprefix=X
mult=1}
C {sky130_fd_pr/res_high_po_2p85.sym} 1130 -460 0 0 {name=R12
W=res_w
L=res_l
model=res_high_po_2p85
spiceprefix=X
mult=1}
C {sky130_fd_pr/res_high_po_2p85.sym} 1280 -460 0 0 {name=R13
W=res_w
L=res_l
model=res_high_po_2p85
spiceprefix=X
mult=1}
C {sky130_fd_pr/res_high_po_2p85.sym} 1490 -460 0 0 {name=R14
W=res_w
L=res_l
model=res_high_po_2p85
spiceprefix=X
mult=1}
C {sky130_fd_pr/res_high_po_2p85.sym} 1640 -460 0 0 {name=R17
W=res_w
L=res_l
model=res_high_po_2p85
spiceprefix=X
mult=1}
C {lab_pin.sym} 460 320 0 0 {name=l114 sig_type=std_logic lab=n5}
C {lab_pin.sym} 610 310 0 0 {name=l115 sig_type=std_logic lab=n6}
C {lab_pin.sym} 1140 340 0 0 {name=l116 sig_type=std_logic lab=n7}
C {lab_pin.sym} 1290 350 0 0 {name=l118 sig_type=std_logic lab=n8}
C {sky130_fd_pr/nfet_01v8_lvt.sym} 430 -310 0 0 {name=M32
L=0.15*wl_scale_nfet
W=1*numf*wl_scale_nfet
nf=1*numf*wl_scale_nfet
mult=1
ad="'int((nf+1)/2) * W/nf * 0.29'" 
pd="'2*int((nf+1)/2) * (W/nf + 0.29)'"
as="'int((nf+2)/2) * W/nf * 0.29'" 
ps="'2*int((nf+2)/2) * (W/nf + 0.29)'"
nrd="'0.29 / W'" nrs="'0.29 / W'"
sa=0 sb=0 sd=0
model=nfet_01v8_lvt
spiceprefix=X
}
C {sky130_fd_pr/nfet_01v8_lvt.sym} 500 -210 0 0 {name=M5
L=0.15*wl_scale_bias
W=1*numf_bias*wl_scale_bias
nf=1*numf_bias*wl_scale_bias
mult=1
ad="'int((nf+1)/2) * W/nf * 0.29'" 
pd="'2*int((nf+1)/2) * (W/nf + 0.29)'"
as="'int((nf+2)/2) * W/nf * 0.29'" 
ps="'2*int((nf+2)/2) * (W/nf + 0.29)'"
nrd="'0.29 / W'" nrs="'0.29 / W'"
sa=0 sb=0 sd=0
model=nfet_01v8_lvt
spiceprefix=X
}
C {sky130_fd_pr/nfet_01v8_lvt.sym} 850 -220 0 0 {name=M1
L=0.15*wl_scale_bias
W=1*numf_bias*wl_scale_bias
nf=1*numf_bias*wl_scale_bias
mult=1
ad="'int((nf+1)/2) * W/nf * 0.29'" 
pd="'2*int((nf+1)/2) * (W/nf + 0.29)'"
as="'int((nf+2)/2) * W/nf * 0.29'" 
ps="'2*int((nf+2)/2) * (W/nf + 0.29)'"
nrd="'0.29 / W'" nrs="'0.29 / W'"
sa=0 sb=0 sd=0
model=nfet_01v8_lvt
spiceprefix=X
}
C {sky130_fd_pr/nfet_01v8_lvt.sym} 1180 -220 0 0 {name=M2
L=0.15*wl_scale_bias
W=1*numf_bias*wl_scale_bias
nf=1*numf_bias*wl_scale_bias
mult=1
ad="'int((nf+1)/2) * W/nf * 0.29'" 
pd="'2*int((nf+1)/2) * (W/nf + 0.29)'"
as="'int((nf+2)/2) * W/nf * 0.29'" 
ps="'2*int((nf+2)/2) * (W/nf + 0.29)'"
nrd="'0.29 / W'" nrs="'0.29 / W'"
sa=0 sb=0 sd=0
model=nfet_01v8_lvt
spiceprefix=X
}
C {sky130_fd_pr/nfet_01v8_lvt.sym} 1540 -220 0 0 {name=M3
L=0.15*wl_scale_bias
W=1*numf_bias*wl_scale_bias
nf=1*numf_bias*wl_scale_bias
mult=1
ad="'int((nf+1)/2) * W/nf * 0.29'" 
pd="'2*int((nf+1)/2) * (W/nf + 0.29)'"
as="'int((nf+2)/2) * W/nf * 0.29'" 
ps="'2*int((nf+2)/2) * (W/nf + 0.29)'"
nrd="'0.29 / W'" nrs="'0.29 / W'"
sa=0 sb=0 sd=0
model=nfet_01v8_lvt
spiceprefix=X
}
C {sky130_fd_pr/nfet_01v8_lvt.sym} 580 -310 0 0 {name=M4
L=0.15*wl_scale_nfet
W=1*numf*wl_scale_nfet
nf=1*numf*wl_scale_nfet
mult=1
ad="'int((nf+1)/2) * W/nf * 0.29'" 
pd="'2*int((nf+1)/2) * (W/nf + 0.29)'"
as="'int((nf+2)/2) * W/nf * 0.29'" 
ps="'2*int((nf+2)/2) * (W/nf + 0.29)'"
nrd="'0.29 / W'" nrs="'0.29 / W'"
sa=0 sb=0 sd=0
model=nfet_01v8_lvt
spiceprefix=X
}
C {sky130_fd_pr/nfet_01v8_lvt.sym} 780 -320 0 0 {name=M6
L=0.15*wl_scale_nfet
W=1*numf*wl_scale_nfet
nf=1*numf*wl_scale_nfet
mult=1
ad="'int((nf+1)/2) * W/nf * 0.29'" 
pd="'2*int((nf+1)/2) * (W/nf + 0.29)'"
as="'int((nf+2)/2) * W/nf * 0.29'" 
ps="'2*int((nf+2)/2) * (W/nf + 0.29)'"
nrd="'0.29 / W'" nrs="'0.29 / W'"
sa=0 sb=0 sd=0
model=nfet_01v8_lvt
spiceprefix=X
}
C {sky130_fd_pr/nfet_01v8_lvt.sym} 930 -320 0 0 {name=M7
L=0.15*wl_scale_nfet
W=1*numf*wl_scale_nfet
nf=1*numf*wl_scale_nfet
mult=1
ad="'int((nf+1)/2) * W/nf * 0.29'" 
pd="'2*int((nf+1)/2) * (W/nf + 0.29)'"
as="'int((nf+2)/2) * W/nf * 0.29'" 
ps="'2*int((nf+2)/2) * (W/nf + 0.29)'"
nrd="'0.29 / W'" nrs="'0.29 / W'"
sa=0 sb=0 sd=0
model=nfet_01v8_lvt
spiceprefix=X
}
C {sky130_fd_pr/nfet_01v8_lvt.sym} 1110 -320 0 0 {name=M8
L=0.15*wl_scale_nfet
W=1*numf*wl_scale_nfet
nf=1*numf*wl_scale_nfet
mult=1
ad="'int((nf+1)/2) * W/nf * 0.29'" 
pd="'2*int((nf+1)/2) * (W/nf + 0.29)'"
as="'int((nf+2)/2) * W/nf * 0.29'" 
ps="'2*int((nf+2)/2) * (W/nf + 0.29)'"
nrd="'0.29 / W'" nrs="'0.29 / W'"
sa=0 sb=0 sd=0
model=nfet_01v8_lvt
spiceprefix=X
}
C {sky130_fd_pr/nfet_01v8_lvt.sym} 1260 -320 0 0 {name=M9
L=0.15*wl_scale_nfet
W=1*numf*wl_scale_nfet
nf=1*numf*wl_scale_nfet
mult=1
ad="'int((nf+1)/2) * W/nf * 0.29'" 
pd="'2*int((nf+1)/2) * (W/nf + 0.29)'"
as="'int((nf+2)/2) * W/nf * 0.29'" 
ps="'2*int((nf+2)/2) * (W/nf + 0.29)'"
nrd="'0.29 / W'" nrs="'0.29 / W'"
sa=0 sb=0 sd=0
model=nfet_01v8_lvt
spiceprefix=X
}
C {sky130_fd_pr/nfet_01v8_lvt.sym} 1470 -320 0 0 {name=M10
L=0.15*wl_scale_nfet
W=1*numf*wl_scale_nfet
nf=1*numf*wl_scale_nfet
mult=1
ad="'int((nf+1)/2) * W/nf * 0.29'" 
pd="'2*int((nf+1)/2) * (W/nf + 0.29)'"
as="'int((nf+2)/2) * W/nf * 0.29'" 
ps="'2*int((nf+2)/2) * (W/nf + 0.29)'"
nrd="'0.29 / W'" nrs="'0.29 / W'"
sa=0 sb=0 sd=0
model=nfet_01v8_lvt
spiceprefix=X
}
C {sky130_fd_pr/nfet_01v8_lvt.sym} 1620 -320 0 0 {name=M11
L=0.15*wl_scale_nfet
W=1*numf*wl_scale_nfet
nf=1*numf*wl_scale_nfet
mult=1
ad="'int((nf+1)/2) * W/nf * 0.29'" 
pd="'2*int((nf+1)/2) * (W/nf + 0.29)'"
as="'int((nf+2)/2) * W/nf * 0.29'" 
ps="'2*int((nf+2)/2) * (W/nf + 0.29)'"
nrd="'0.29 / W'" nrs="'0.29 / W'"
sa=0 sb=0 sd=0
model=nfet_01v8_lvt
spiceprefix=X
}
C {sky130_fd_pr/nfet_01v8_lvt.sym} 1630 400 0 0 {name=M12
L=0.15*wl_scale_nfet
W=1*numf*wl_scale_nfet
nf=1*numf*wl_scale_nfet
mult=1
ad="'int((nf+1)/2) * W/nf * 0.29'" 
pd="'2*int((nf+1)/2) * (W/nf + 0.29)'"
as="'int((nf+2)/2) * W/nf * 0.29'" 
ps="'2*int((nf+2)/2) * (W/nf + 0.29)'"
nrd="'0.29 / W'" nrs="'0.29 / W'"
sa=0 sb=0 sd=0
model=nfet_01v8_lvt
spiceprefix=X
}
C {sky130_fd_pr/nfet_01v8_lvt.sym} 1480 400 0 0 {name=M17
L=0.15*wl_scale_nfet
W=1*numf*wl_scale_nfet
nf=1*numf*wl_scale_nfet
mult=1
ad="'int((nf+1)/2) * W/nf * 0.29'" 
pd="'2*int((nf+1)/2) * (W/nf + 0.29)'"
as="'int((nf+2)/2) * W/nf * 0.29'" 
ps="'2*int((nf+2)/2) * (W/nf + 0.29)'"
nrd="'0.29 / W'" nrs="'0.29 / W'"
sa=0 sb=0 sd=0
model=nfet_01v8_lvt
spiceprefix=X
}
C {sky130_fd_pr/nfet_01v8_lvt.sym} 1270 400 0 0 {name=M18
L=0.15*wl_scale_nfet
W=1*numf*wl_scale_nfet
nf=1*numf*wl_scale_nfet
mult=1
ad="'int((nf+1)/2) * W/nf * 0.29'" 
pd="'2*int((nf+1)/2) * (W/nf + 0.29)'"
as="'int((nf+2)/2) * W/nf * 0.29'" 
ps="'2*int((nf+2)/2) * (W/nf + 0.29)'"
nrd="'0.29 / W'" nrs="'0.29 / W'"
sa=0 sb=0 sd=0
model=nfet_01v8_lvt
spiceprefix=X
}
C {sky130_fd_pr/nfet_01v8_lvt.sym} 1120 400 0 0 {name=M19
L=0.15*wl_scale_nfet
W=1*numf*wl_scale_nfet
nf=1*numf*wl_scale_nfet
mult=1
ad="'int((nf+1)/2) * W/nf * 0.29'" 
pd="'2*int((nf+1)/2) * (W/nf + 0.29)'"
as="'int((nf+2)/2) * W/nf * 0.29'" 
ps="'2*int((nf+2)/2) * (W/nf + 0.29)'"
nrd="'0.29 / W'" nrs="'0.29 / W'"
sa=0 sb=0 sd=0
model=nfet_01v8_lvt
spiceprefix=X
}
C {sky130_fd_pr/nfet_01v8_lvt.sym} 940 400 0 0 {name=M20
L=0.15*wl_scale_nfet
W=1*numf*wl_scale_nfet
nf=1*numf*wl_scale_nfet
mult=1
ad="'int((nf+1)/2) * W/nf * 0.29'" 
pd="'2*int((nf+1)/2) * (W/nf + 0.29)'"
as="'int((nf+2)/2) * W/nf * 0.29'" 
ps="'2*int((nf+2)/2) * (W/nf + 0.29)'"
nrd="'0.29 / W'" nrs="'0.29 / W'"
sa=0 sb=0 sd=0
model=nfet_01v8_lvt
spiceprefix=X
}
C {sky130_fd_pr/nfet_01v8_lvt.sym} 790 400 0 0 {name=M21
L=0.15*wl_scale_nfet
W=1*numf*wl_scale_nfet
nf=1*numf*wl_scale_nfet
mult=1
ad="'int((nf+1)/2) * W/nf * 0.29'" 
pd="'2*int((nf+1)/2) * (W/nf + 0.29)'"
as="'int((nf+2)/2) * W/nf * 0.29'" 
ps="'2*int((nf+2)/2) * (W/nf + 0.29)'"
nrd="'0.29 / W'" nrs="'0.29 / W'"
sa=0 sb=0 sd=0
model=nfet_01v8_lvt
spiceprefix=X
}
C {sky130_fd_pr/nfet_01v8_lvt.sym} 590 410 0 0 {name=M22
L=0.15*wl_scale_nfet
W=1*numf*wl_scale_nfet
nf=1*numf*wl_scale_nfet
mult=1
ad="'int((nf+1)/2) * W/nf * 0.29'" 
pd="'2*int((nf+1)/2) * (W/nf + 0.29)'"
as="'int((nf+2)/2) * W/nf * 0.29'" 
ps="'2*int((nf+2)/2) * (W/nf + 0.29)'"
nrd="'0.29 / W'" nrs="'0.29 / W'"
sa=0 sb=0 sd=0
model=nfet_01v8_lvt
spiceprefix=X
}
C {sky130_fd_pr/nfet_01v8_lvt.sym} 440 410 0 0 {name=M23
L=0.15*wl_scale_nfet
W=1*numf*wl_scale_nfet
nf=1*numf*wl_scale_nfet
mult=1
ad="'int((nf+1)/2) * W/nf * 0.29'" 
pd="'2*int((nf+1)/2) * (W/nf + 0.29)'"
as="'int((nf+2)/2) * W/nf * 0.29'" 
ps="'2*int((nf+2)/2) * (W/nf + 0.29)'"
nrd="'0.29 / W'" nrs="'0.29 / W'"
sa=0 sb=0 sd=0
model=nfet_01v8_lvt
spiceprefix=X
}
C {sky130_fd_pr/nfet_01v8_lvt.sym} 400 930 0 0 {name=M24
L=0.15
W=8
nf=8
mult=1
ad="'int((nf+1)/2) * W/nf * 0.29'" 
pd="'2*int((nf+1)/2) * (W/nf + 0.29)'"
as="'int((nf+2)/2) * W/nf * 0.29'" 
ps="'2*int((nf+2)/2) * (W/nf + 0.29)'"
nrd="'0.29 / W'" nrs="'0.29 / W'"
sa=0 sb=0 sd=0
model=nfet_01v8_lvt
spiceprefix=X
}
C {sky130_fd_pr/nfet_01v8_lvt.sym} 600 920 0 0 {name=M29
L=0.15
W=8
nf=8
mult=1
ad="'int((nf+1)/2) * W/nf * 0.29'" 
pd="'2*int((nf+1)/2) * (W/nf + 0.29)'"
as="'int((nf+2)/2) * W/nf * 0.29'" 
ps="'2*int((nf+2)/2) * (W/nf + 0.29)'"
nrd="'0.29 / W'" nrs="'0.29 / W'"
sa=0 sb=0 sd=0
model=nfet_01v8_lvt
spiceprefix=X
}
C {sky130_fd_pr/nfet_01v8_lvt.sym} 750 920 0 0 {name=M30
L=0.15
W=8
nf=8
mult=1
ad="'int((nf+1)/2) * W/nf * 0.29'" 
pd="'2*int((nf+1)/2) * (W/nf + 0.29)'"
as="'int((nf+2)/2) * W/nf * 0.29'" 
ps="'2*int((nf+2)/2) * (W/nf + 0.29)'"
nrd="'0.29 / W'" nrs="'0.29 / W'"
sa=0 sb=0 sd=0
model=nfet_01v8_lvt
spiceprefix=X
}
C {vsource.sym} -90 -330 0 0 {name=V22 value="dc 0 PWL 0ns 0 40ns 0 40.001ns 2.8 80ns 2.8 r=0" 
}
C {gnd.sym} -90 -300 0 0 {name=l117 lab=GND}
C {gnd.sym} -90 -210 0 0 {name=l119 lab=GND}
C {gnd.sym} -90 -120 0 0 {name=l120 lab=GND}
C {gnd.sym} -90 -30 0 0 {name=l130 lab=GND}
C {gnd.sym} -90 60 0 0 {name=l131 lab=GND}
C {lab_pin.sym} -90 -360 0 0 {name=l132 sig_type=std_logic lab=CTRL1
}
C {lab_pin.sym} -90 -270 0 0 {name=l133 sig_type=std_logic lab=CTRL2
}
C {lab_pin.sym} -90 -180 0 0 {name=l153 sig_type=std_logic lab=CTRL3
}
C {lab_pin.sym} -90 -90 0 0 {name=l164 sig_type=std_logic lab=CTRL4
}
C {lab_pin.sym} -90 0 0 0 {name=l165 sig_type=std_logic lab=CTRL5
}
C {vsource.sym} -90 -240 0 0 {name=V23 value="dc 0 PWL 0ns 0 80ns 0 80.001ns 2.8 160ns 2.8 r=0" 
}
C {vsource.sym} -90 -150 0 0 {name=V24 value="dc 0 PWL 0ns 0 160ns 0 160.001ns 2.8 320ns 2.8 r=0" 
}
C {vsource.sym} -90 -60 0 0 {name=V25 value="dc 0 PWL 0ns 0 320ns 0 320.001ns 2.8 640ns 2.8 r=0" 
}
C {vsource.sym} -90 30 0 0 {name=V26 value="dc 0 PWL 0ns 0 640ns 0 640.001ns 2.8 r=0" 
}
C {code_shown.sym} 2260 30 0 0 {name=spice2 only_toplevel=false value="
.option
.control
*let startv = 0.2
*let endv = 0.8
*let incre = 0.05
*let curv = startv
*while curv le endv
*alter v17 curv
*tran 0.1n 1280n
*write tran.out test3 n5 n5-n6
*set appendwrite
*let curv = curv + incre
*end
*plot tran1.n5 tran2.n5 tran3.n5 tran4.n5 tran5.n5 tran6.n5 tran7.n5 tran8.n5 tran9.n5 tran10.n5
*plot vbiasn2 tran1.test3 tran2.test3 tran3.test3 tran4.test3 tran5.test3 tran6.test3 tran7.test3 tran8.test3 tran9.test3 tran10.test3
.endc
"}
